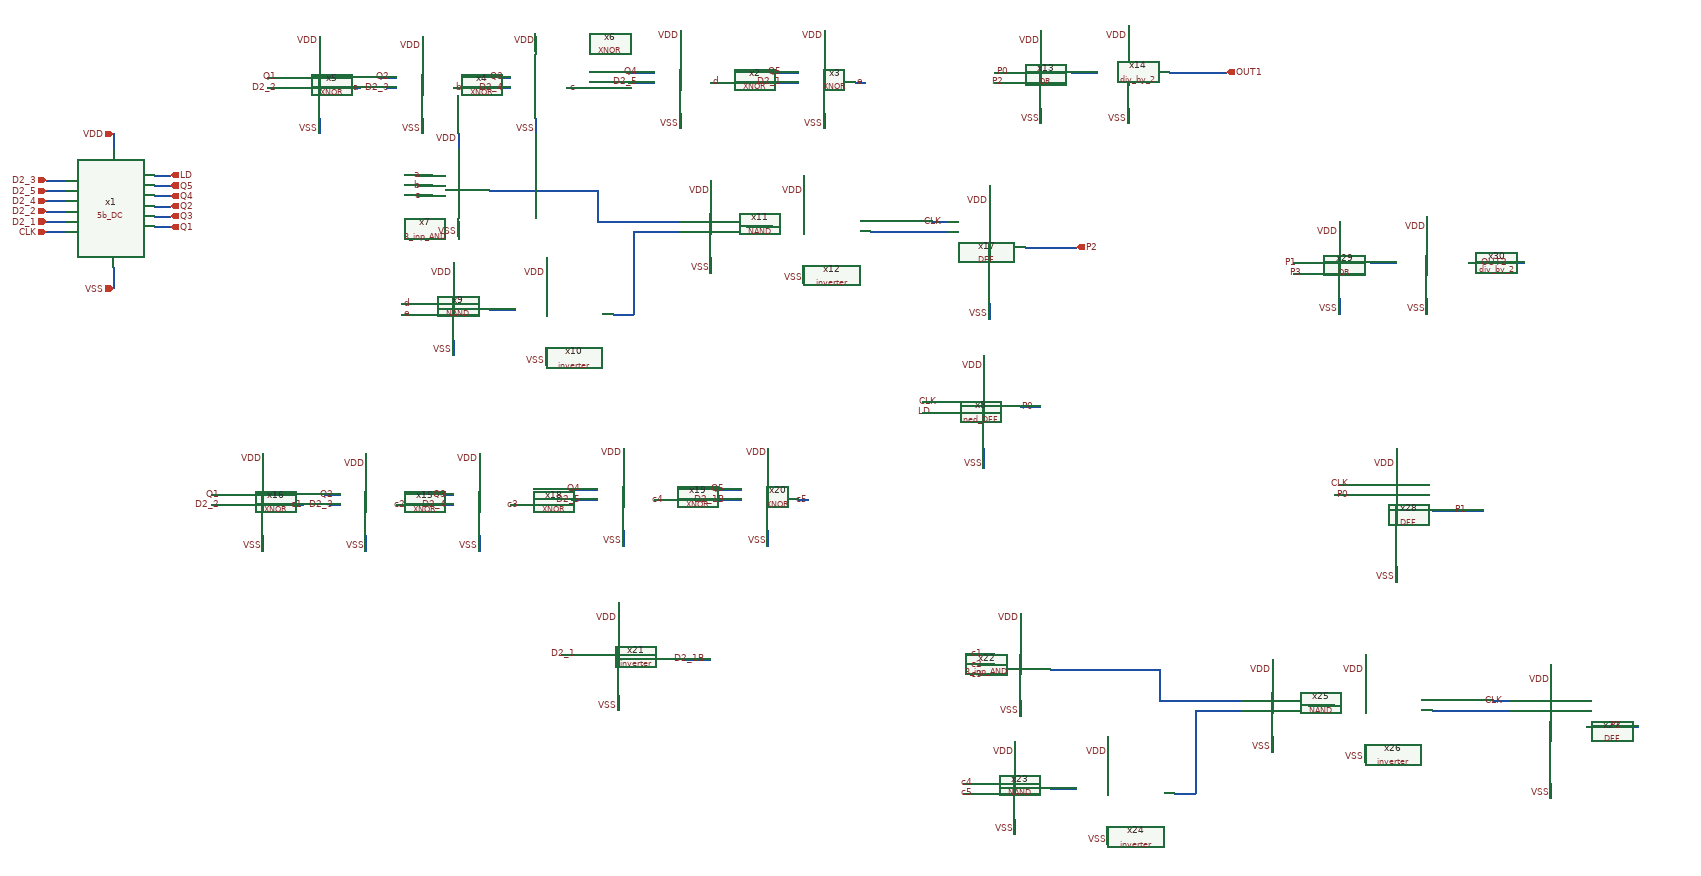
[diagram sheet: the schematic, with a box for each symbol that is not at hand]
v {xschem version=3.1.0 file_version=1.2
}
G {}
K {}
V {}
S {}
E {}
N -210 -200 -210 -170 {
lab=VDD}
N -210 60 -210 100 {
lab=VSS}
N -340 -110 -300 -110 {
lab=D2_3}
N -340 -90 -300 -90 {
lab=D2_5}
N -340 -70 -300 -70 {
lab=D2_4}
N -340 -50 -300 -50 {
lab=D2_2}
N -340 -30 -300 -30 {
lab=D2_1}
N -340 -10 -300 -10 {
lab=CLK}
N -130 -120 -100 -120 {
lab=LD}
N -130 -100 -100 -100 {
lab=Q5}
N -130 -80 -100 -80 {
lab=Q4}
N -130 -60 -100 -60 {
lab=Q2}
N -130 -40 -100 -40 {
lab=Q3}
N -130 -20 -100 -20 {
lab=Q1}
N 90 -310 140 -310 {
lab=Q1}
N 90 -290 140 -290 {
lab=D2_2}
N 310 -310 340 -310 {
lab=Q2}
N 320 -290 340 -290 {
lab=D2_3}
N 540 -310 560 -310 {
lab=Q3}
N 540 -290 560 -290 {
lab=D2_4}
N 450 -290 480 -290 {
lab=b}
N 190 -390 190 -360 {
lab=VDD}
N 190 -230 190 -200 {
lab=VSS}
N 390 -390 390 -360 {
lab=VDD}
N 390 -230 390 -200 {
lab=VSS}
N 610 -390 610 -360 {
lab=VDD}
N 610 -230 610 -200 {
lab=VSS}
N 670 -290 700 -290 {
lab=c}
N 250 -290 270 -290 {
lab=a}
N 380 -120 410 -120 {
lab=a}
N 380 -100 410 -100 {
lab=b}
N 380 -80 410 -80 {
lab=c}
N 460 -200 460 -170 {
lab=VDD}
N 460 -30 460 0 {
lab=VSS}
N 520 -90 550 -90 {
lab=#net1}
N 550 -90 590 -90 {
lab=#net1}
N 790 -320 840 -320 {
lab=Q4}
N 790 -300 840 -300 {
lab=D2_5}
N 890 -400 890 -370 {
lab=VDD}
N 890 -240 890 -210 {
lab=VSS}
N 950 -300 970 -300 {
lab=d}
N 1070 -320 1120 -320 {
lab=Q5}
N 1070 -300 1120 -300 {
lab=D2_1}
N 1170 -400 1170 -370 {
lab=VDD}
N 1170 -240 1170 -210 {
lab=VSS}
N 1230 -300 1250 -300 {
lab=e}
N 520 140 570 140 {
lab=#net2}
N 450 50 450 80 {
lab=VDD}
N 450 200 450 230 {
lab=VSS}
N 630 40 630 80 {
lab=VDD}
N 760 150 800 150 {
lab=#net3}
N 630 220 630 250 {
lab=VSS}
N 350 130 390 130 {
lab=d}
N 350 150 390 150 {
lab=e}
N 1020 -20 1070 -20 {
lab=#net4}
N 950 -110 950 -80 {
lab=VDD}
N 950 40 950 70 {
lab=VSS}
N 1130 -120 1130 -80 {
lab=VDD}
N 1260 -10 1300 -10 {
lab=#net5}
N 1130 60 1130 90 {
lab=VSS}
N 850 -30 890 -30 {
lab=#net1}
N 850 -10 890 -10 {
lab=#net3}
N 590 -90 730 -90 {
lab=#net1}
N 730 -90 730 -30 {
lab=#net1}
N 730 -30 850 -30 {
lab=#net1}
N 800 -10 800 150 {
lab=#net3}
N 800 -10 850 -10 {
lab=#net3}
N 1300 -10 1410 -10 {
lab=#net5}
N 1500 -320 1540 -320 {
lab=P0}
N 1500 -300 1540 -300 {
lab=P2}
N 1590 -400 1590 -370 {
lab=VDD}
N 1590 -250 1590 -220 {
lab=VSS}
N 1650 -320 1700 -320 {
lab=#net6}
N 1760 -410 1760 -380 {
lab=VDD}
N 1760 -250 1760 -220 {
lab=VSS}
N 1840 -320 1880 -320 {
lab=OUT1}
N 1880 -320 1950 -320 {
lab=OUT1}
N 1620 20 1660 20 {
lab=P2}
N 1360 320 1410 320 {
lab=CLK}
N 1360 340 1410 340 {
lab=LD}
N 1480 230 1480 260 {
lab=VDD}
N 1480 410 1480 450 {
lab=VSS}
N 1550 330 1590 330 {
lab=P0}
N 1560 20 1620 20 {
lab=P2}
N 1380 -30 1410 -30 {
lab=CLK}
N 1490 -100 1490 -60 {
lab=VDD}
N 1490 130 1490 160 {
lab=VSS}
N -20 500 30 500 {
lab=Q1}
N -20 520 30 520 {
lab=D2_2}
N 200 500 230 500 {
lab=Q2}
N 210 520 230 520 {
lab=D2_3}
N 430 500 450 500 {
lab=Q3}
N 430 520 450 520 {
lab=D2_4}
N 340 520 370 520 {
lab=c2}
N 80 420 80 450 {
lab=VDD}
N 80 580 80 610 {
lab=VSS}
N 280 420 280 450 {
lab=VDD}
N 280 580 280 610 {
lab=VSS}
N 500 420 500 450 {
lab=VDD}
N 500 580 500 610 {
lab=VSS}
N 560 520 590 520 {
lab=c3}
N 140 520 160 520 {
lab=c1}
N 680 490 730 490 {
lab=Q4}
N 680 510 730 510 {
lab=D2_5}
N 780 410 780 440 {
lab=VDD}
N 780 570 780 600 {
lab=VSS}
N 840 510 860 510 {
lab=c4}
N 960 490 1010 490 {
lab=Q5}
N 960 510 1010 510 {
lab=D2_1B}
N 1060 410 1060 440 {
lab=VDD}
N 1060 570 1060 600 {
lab=VSS}
N 1120 510 1140 510 {
lab=c5}
N 770 710 770 750 {
lab=VDD}
N 770 890 770 920 {
lab=VSS}
N 660 810 710 810 {
lab=D2_1}
N 900 820 950 820 {
lab=D2_1B}
N 1470 810 1500 810 {
lab=c1}
N 1470 830 1500 830 {
lab=c2}
N 1470 850 1500 850 {
lab=c3}
N 1550 730 1550 760 {
lab=VDD}
N 1550 900 1550 930 {
lab=VSS}
N 1610 840 1640 840 {
lab=#net7}
N 1640 840 1680 840 {
lab=#net7}
N 1610 1070 1660 1070 {
lab=#net8}
N 1540 980 1540 1010 {
lab=VDD}
N 1540 1130 1540 1160 {
lab=VSS}
N 1720 970 1720 1010 {
lab=VDD}
N 1850 1080 1890 1080 {
lab=#net9}
N 1720 1150 1720 1180 {
lab=VSS}
N 1440 1060 1480 1060 {
lab=c4}
N 1440 1080 1480 1080 {
lab=c5}
N 2110 910 2160 910 {
lab=#net10}
N 2040 820 2040 850 {
lab=VDD}
N 2040 970 2040 1000 {
lab=VSS}
N 2220 810 2220 850 {
lab=VDD}
N 2350 920 2390 920 {
lab=#net11}
N 2220 990 2220 1020 {
lab=VSS}
N 1940 900 1980 900 {
lab=#net7}
N 1940 920 1980 920 {
lab=#net9}
N 1680 840 1820 840 {
lab=#net7}
N 1820 840 1820 900 {
lab=#net7}
N 1820 900 1940 900 {
lab=#net7}
N 1890 920 1890 1080 {
lab=#net9}
N 1890 920 1940 920 {
lab=#net9}
N 2390 920 2500 920 {
lab=#net11}
N 2710 950 2750 950 {
lab=P3}
N 2650 950 2710 950 {
lab=P3}
N 2470 900 2500 900 {
lab=CLK}
N 2580 830 2580 870 {
lab=VDD}
N 2580 1060 2580 1090 {
lab=VSS}
N 2410 530 2450 530 {
lab=P1}
N 2350 530 2410 530 {
lab=P1}
N 2170 480 2200 480 {
lab=CLK}
N 2280 410 2280 450 {
lab=VDD}
N 2280 640 2280 670 {
lab=VSS}
N 2160 500 2200 500 {
lab=P0}
N 2080 50 2120 50 {
lab=P1}
N 2080 70 2120 70 {
lab=P3}
N 2170 -30 2170 0 {
lab=VDD}
N 2170 120 2170 150 {
lab=VSS}
N 2230 50 2280 50 {
lab=#net12}
N 2340 -40 2340 -10 {
lab=VDD}
N 2340 120 2340 150 {
lab=VSS}
N 2420 50 2460 50 {
lab=OUT2}
N 2460 50 2530 50 {
lab=OUT2}
C {5b_DC.sym} -150 -40 0 0 {name=x1}
C {devices/iopin.sym} -210 -200 3 0 {name=p1 lab=VDD}
C {devices/iopin.sym} -210 100 1 0 {name=p2 lab=VSS}
C {devices/ipin.sym} -340 -10 0 0 {name=p3 lab=CLK}
C {devices/ipin.sym} -340 -30 0 0 {name=p4 lab=D2_1}
C {devices/ipin.sym} -340 -50 0 0 {name=p5 lab=D2_2}
C {devices/ipin.sym} -340 -110 0 0 {name=p6 lab=D2_3}
C {devices/ipin.sym} -340 -70 0 0 {name=p7 lab=D2_4}
C {devices/ipin.sym} -340 -90 0 0 {name=p8 lab=D2_5}
C {devices/opin.sym} -100 -120 0 0 {name=p9 lab=LD}
C {devices/opin.sym} -100 -100 0 0 {name=p10 lab=Q5}
C {devices/opin.sym} -100 -80 0 0 {name=p11 lab=Q4}
C {devices/opin.sym} -100 -60 0 0 {name=p12 lab=Q2}
C {devices/opin.sym} -100 -40 0 0 {name=p13 lab=Q3}
C {devices/opin.sym} -100 -20 0 0 {name=p14 lab=Q1}
C {XNOR.sym} 490 -290 0 0 {name=x4}
C {XNOR.sym} 290 -290 0 0 {name=x5}
C {XNOR.sym} 710 -290 0 0 {name=x6}
C {devices/lab_wire.sym} 190 -380 0 0 {name=p17 sig_type=std_logic lab=VDD}
C {devices/lab_wire.sym} 390 -370 0 0 {name=p18 sig_type=std_logic lab=VDD}
C {devices/lab_wire.sym} 610 -380 0 0 {name=p19 sig_type=std_logic lab=VDD}
C {devices/lab_wire.sym} 190 -210 0 0 {name=p20 sig_type=std_logic lab=VSS}
C {devices/lab_wire.sym} 390 -210 0 0 {name=p21 sig_type=std_logic lab=VSS}
C {devices/lab_wire.sym} 610 -210 0 0 {name=p22 sig_type=std_logic lab=VSS}
C {devices/lab_wire.sym} 110 -310 0 0 {name=p26 sig_type=std_logic lab=Q1}
C {devices/lab_wire.sym} 330 -310 0 0 {name=p27 sig_type=std_logic lab=Q2}
C {devices/lab_wire.sym} 550 -310 0 0 {name=p28 sig_type=std_logic lab=Q3}
C {devices/lab_wire.sym} 550 -290 0 0 {name=p29 sig_type=std_logic lab=D2_4}
C {devices/lab_wire.sym} 330 -290 0 0 {name=p30 sig_type=std_logic lab=D2_3}
C {devices/lab_wire.sym} 110 -290 0 0 {name=p31 sig_type=std_logic lab=D2_2}
C {3_inp_AND.sym} 560 -100 0 0 {name=x7}
C {devices/lab_wire.sym} 460 -190 0 0 {name=p32 sig_type=std_logic lab=VDD}
C {devices/lab_wire.sym} 460 -10 0 0 {name=p33 sig_type=std_logic lab=VSS}
C {devices/lab_wire.sym} 270 -290 0 0 {name=p34 sig_type=std_logic lab=a}
C {devices/lab_wire.sym} 470 -290 0 0 {name=p35 sig_type=std_logic lab=b}
C {devices/lab_wire.sym} 690 -290 0 0 {name=p36 sig_type=std_logic lab=c}
C {devices/lab_wire.sym} 390 -120 0 0 {name=p37 sig_type=std_logic lab=a}
C {devices/lab_wire.sym} 390 -100 0 0 {name=p38 sig_type=std_logic lab=b}
C {devices/lab_wire.sym} 390 -80 0 0 {name=p39 sig_type=std_logic lab=c}
C {XNOR.sym} 990 -300 0 0 {name=x2}
C {devices/lab_wire.sym} 890 -390 0 0 {name=p15 sig_type=std_logic lab=VDD}
C {devices/lab_wire.sym} 890 -220 0 0 {name=p16 sig_type=std_logic lab=VSS}
C {devices/lab_wire.sym} 810 -320 0 0 {name=p23 sig_type=std_logic lab=Q4}
C {devices/lab_wire.sym} 810 -300 0 0 {name=p24 sig_type=std_logic lab=D2_5}
C {devices/lab_wire.sym} 970 -300 0 0 {name=p25 sig_type=std_logic lab=d}
C {XNOR.sym} 1270 -300 0 0 {name=x3}
C {devices/lab_wire.sym} 1170 -390 0 0 {name=p44 sig_type=std_logic lab=VDD}
C {devices/lab_wire.sym} 1170 -220 0 0 {name=p45 sig_type=std_logic lab=VSS}
C {devices/lab_wire.sym} 1090 -320 0 0 {name=p46 sig_type=std_logic lab=Q5}
C {devices/lab_wire.sym} 1090 -300 0 0 {name=p47 sig_type=std_logic lab=D2_1}
C {devices/lab_wire.sym} 1250 -300 0 0 {name=p48 sig_type=std_logic lab=e}
C {NAND.sym} 540 150 0 0 {name=x9}
C {inverter.sym} 720 160 0 0 {name=x10}
C {devices/lab_wire.sym} 450 70 0 0 {name=p49 sig_type=std_logic lab=VDD}
C {devices/lab_wire.sym} 450 220 0 0 {name=p50 sig_type=std_logic lab=VSS}
C {devices/lab_wire.sym} 630 70 0 0 {name=p51 sig_type=std_logic lab=VDD}
C {devices/lab_wire.sym} 630 240 0 0 {name=p52 sig_type=std_logic lab=VSS}
C {devices/lab_wire.sym} 370 130 0 0 {name=p53 sig_type=std_logic lab=d}
C {devices/lab_wire.sym} 370 150 0 0 {name=p54 sig_type=std_logic lab=e}
C {NAND.sym} 1040 -10 0 0 {name=x11}
C {inverter.sym} 1220 0 0 0 {name=x12}
C {devices/lab_wire.sym} 950 -90 0 0 {name=p55 sig_type=std_logic lab=VDD}
C {devices/lab_wire.sym} 950 60 0 0 {name=p56 sig_type=std_logic lab=VSS}
C {devices/lab_wire.sym} 1130 -90 0 0 {name=p57 sig_type=std_logic lab=VDD}
C {devices/lab_wire.sym} 1130 80 0 0 {name=p58 sig_type=std_logic lab=VSS}
C {OR.sym} 1690 -300 0 0 {name=x13}
C {devices/lab_wire.sym} 1520 -300 0 0 {name=p60 sig_type=std_logic lab=P2}
C {devices/lab_wire.sym} 1590 -380 0 0 {name=p61 sig_type=std_logic lab=VDD}
C {devices/lab_wire.sym} 1590 -230 0 0 {name=p62 sig_type=std_logic lab=VSS}
C {div_by_2.sym} 1850 -300 0 0 {name=x14}
C {devices/lab_wire.sym} 1760 -390 0 0 {name=p63 sig_type=std_logic lab=VDD}
C {devices/lab_wire.sym} 1760 -230 0 0 {name=p64 sig_type=std_logic lab=VSS}
C {devices/opin.sym} 1950 -320 0 0 {name=p65 lab=OUT1}
C {devices/opin.sym} 1660 20 0 0 {name=p40 lab=P2}
C {devices/lab_wire.sym} 1530 -320 0 0 {name=p67 sig_type=std_logic lab=P0}
C {devices/lab_wire.sym} 1580 330 0 0 {name=p59 sig_type=std_logic lab=P0}
C {devices/lab_wire.sym} 1380 340 0 0 {name=p41 sig_type=std_logic lab=LD}
C {devices/lab_wire.sym} 1480 250 0 0 {name=p42 sig_type=std_logic lab=VDD}
C {devices/lab_wire.sym} 1480 440 0 0 {name=p43 sig_type=std_logic lab=VSS}
C {devices/lab_wire.sym} 1390 320 0 0 {name=p66 sig_type=std_logic lab=CLK}
C {DFF.sym} 1560 -10 0 0 {name=x17}
C {devices/lab_wire.sym} 1400 -30 0 0 {name=p72 sig_type=std_logic lab=CLK}
C {devices/lab_wire.sym} 1490 -70 0 0 {name=p73 sig_type=std_logic lab=VDD}
C {devices/lab_wire.sym} 1490 150 0 0 {name=p74 sig_type=std_logic lab=VSS}
C {ned_DFF.sym} 1560 340 0 0 {name=x8}
C {XNOR.sym} 380 520 0 0 {name=x15}
C {XNOR.sym} 180 520 0 0 {name=x16}
C {XNOR.sym} 600 520 0 0 {name=x18}
C {devices/lab_wire.sym} 80 430 0 0 {name=p68 sig_type=std_logic lab=VDD}
C {devices/lab_wire.sym} 280 440 0 0 {name=p69 sig_type=std_logic lab=VDD}
C {devices/lab_wire.sym} 500 430 0 0 {name=p70 sig_type=std_logic lab=VDD}
C {devices/lab_wire.sym} 80 600 0 0 {name=p71 sig_type=std_logic lab=VSS}
C {devices/lab_wire.sym} 280 600 0 0 {name=p75 sig_type=std_logic lab=VSS}
C {devices/lab_wire.sym} 500 600 0 0 {name=p76 sig_type=std_logic lab=VSS}
C {devices/lab_wire.sym} 0 500 0 0 {name=p77 sig_type=std_logic lab=Q1}
C {devices/lab_wire.sym} 220 500 0 0 {name=p78 sig_type=std_logic lab=Q2}
C {devices/lab_wire.sym} 440 500 0 0 {name=p79 sig_type=std_logic lab=Q3}
C {devices/lab_wire.sym} 440 520 0 0 {name=p80 sig_type=std_logic lab=D2_4}
C {devices/lab_wire.sym} 220 520 0 0 {name=p81 sig_type=std_logic lab=D2_3}
C {devices/lab_wire.sym} 0 520 0 0 {name=p82 sig_type=std_logic lab=D2_2}
C {devices/lab_wire.sym} 160 520 0 0 {name=p84 sig_type=std_logic lab=c1}
C {devices/lab_wire.sym} 360 520 0 0 {name=p85 sig_type=std_logic lab=c2}
C {devices/lab_wire.sym} 580 520 0 0 {name=p86 sig_type=std_logic lab=c3}
C {XNOR.sym} 880 510 0 0 {name=x19}
C {devices/lab_wire.sym} 780 420 0 0 {name=p87 sig_type=std_logic lab=VDD}
C {devices/lab_wire.sym} 780 590 0 0 {name=p88 sig_type=std_logic lab=VSS}
C {devices/lab_wire.sym} 700 490 0 0 {name=p89 sig_type=std_logic lab=Q4}
C {devices/lab_wire.sym} 700 510 0 0 {name=p90 sig_type=std_logic lab=D2_5}
C {devices/lab_wire.sym} 860 510 0 0 {name=p91 sig_type=std_logic lab=c4}
C {XNOR.sym} 1160 510 0 0 {name=x20}
C {devices/lab_wire.sym} 1060 420 0 0 {name=p92 sig_type=std_logic lab=VDD}
C {devices/lab_wire.sym} 1060 590 0 0 {name=p93 sig_type=std_logic lab=VSS}
C {devices/lab_wire.sym} 980 490 0 0 {name=p94 sig_type=std_logic lab=Q5}
C {devices/lab_wire.sym} 980 510 0 0 {name=p95 sig_type=std_logic lab=D2_1B}
C {devices/lab_wire.sym} 1140 510 0 0 {name=p96 sig_type=std_logic lab=c5}
C {inverter.sym} 860 830 0 0 {name=x21}
C {devices/lab_wire.sym} 770 740 0 0 {name=p83 sig_type=std_logic lab=VDD}
C {devices/lab_wire.sym} 770 910 0 0 {name=p97 sig_type=std_logic lab=VSS}
C {devices/lab_wire.sym} 940 820 0 0 {name=p98 sig_type=std_logic lab=D2_1B}
C {devices/lab_wire.sym} 690 810 0 0 {name=p99 sig_type=std_logic lab=D2_1}
C {3_inp_AND.sym} 1650 830 0 0 {name=x22}
C {devices/lab_wire.sym} 1550 740 0 0 {name=p102 sig_type=std_logic lab=VDD}
C {devices/lab_wire.sym} 1550 920 0 0 {name=p103 sig_type=std_logic lab=VSS}
C {NAND.sym} 1630 1080 0 0 {name=x23}
C {inverter.sym} 1810 1090 0 0 {name=x24}
C {devices/lab_wire.sym} 1540 1000 0 0 {name=p107 sig_type=std_logic lab=VDD}
C {devices/lab_wire.sym} 1540 1150 0 0 {name=p108 sig_type=std_logic lab=VSS}
C {devices/lab_wire.sym} 1720 1000 0 0 {name=p109 sig_type=std_logic lab=VDD}
C {devices/lab_wire.sym} 1720 1170 0 0 {name=p110 sig_type=std_logic lab=VSS}
C {NAND.sym} 2130 920 0 0 {name=x25}
C {inverter.sym} 2310 930 0 0 {name=x26}
C {devices/lab_wire.sym} 2040 840 0 0 {name=p113 sig_type=std_logic lab=VDD}
C {devices/lab_wire.sym} 2040 990 0 0 {name=p114 sig_type=std_logic lab=VSS}
C {devices/lab_wire.sym} 2220 840 0 0 {name=p115 sig_type=std_logic lab=VDD}
C {devices/lab_wire.sym} 2220 1010 0 0 {name=p116 sig_type=std_logic lab=VSS}
C {DFF.sym} 2650 920 0 0 {name=x27}
C {devices/lab_wire.sym} 2490 900 0 0 {name=p119 sig_type=std_logic lab=CLK}
C {devices/lab_wire.sym} 2580 860 0 0 {name=p120 sig_type=std_logic lab=VDD}
C {devices/lab_wire.sym} 2580 1080 0 0 {name=p121 sig_type=std_logic lab=VSS}
C {devices/lab_wire.sym} 1480 810 0 0 {name=p100 sig_type=std_logic lab=c1}
C {devices/lab_wire.sym} 1480 830 0 0 {name=p101 sig_type=std_logic lab=c2}
C {devices/lab_wire.sym} 1480 850 0 0 {name=p104 sig_type=std_logic lab=c3}
C {devices/lab_wire.sym} 1460 1060 0 0 {name=p105 sig_type=std_logic lab=c4}
C {devices/lab_wire.sym} 1460 1080 0 0 {name=p106 sig_type=std_logic lab=c5}
C {devices/lab_wire.sym} 2720 950 0 0 {name=p111 sig_type=std_logic lab=P3}
C {DFF.sym} 2350 500 0 0 {name=x28}
C {devices/lab_wire.sym} 2190 480 0 0 {name=p112 sig_type=std_logic lab=CLK}
C {devices/lab_wire.sym} 2280 440 0 0 {name=p117 sig_type=std_logic lab=VDD}
C {devices/lab_wire.sym} 2280 660 0 0 {name=p118 sig_type=std_logic lab=VSS}
C {devices/lab_wire.sym} 2420 530 0 0 {name=p122 sig_type=std_logic lab=P1}
C {OR.sym} 2270 70 0 0 {name=x29}
C {devices/lab_wire.sym} 2170 -10 0 0 {name=p125 sig_type=std_logic lab=VDD}
C {devices/lab_wire.sym} 2170 140 0 0 {name=p126 sig_type=std_logic lab=VSS}
C {div_by_2.sym} 2430 70 0 0 {name=x30}
C {devices/lab_wire.sym} 2340 -20 0 0 {name=p127 sig_type=std_logic lab=VDD}
C {devices/lab_wire.sym} 2340 140 0 0 {name=p128 sig_type=std_logic lab=VSS}
C {devices/lab_wire.sym} 2100 70 0 0 {name=p124 sig_type=std_logic lab=P3}
C {devices/lab_wire.sym} 2090 50 0 0 {name=p130 sig_type=std_logic lab=P1}
C {devices/lab_wire.sym} 2500 50 0 0 {name=p129 sig_type=std_logic lab=OUT2}
C {devices/lab_wire.sym} 2190 500 0 0 {name=p123 sig_type=std_logic lab=P0}
